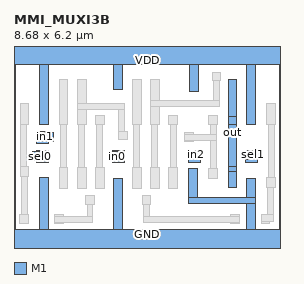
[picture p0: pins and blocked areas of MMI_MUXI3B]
MACRO MMI_MUXI3B
	CLASS CORE ;
	FOREIGN MMI_MUXI3B 0 0 ;
	SIZE 8.68 BY 6.2 ;
	SYMMETRY X Y ;
	SITE CORE1 ;
	PIN out
		DIRECTION output ;
		USE SIGNAL ;
		PORT
			LAYER M1 ;
			RECT 6.995 4.1 7.275 5.29 ;
			LAYER M1 ;
			RECT 6.985 3.82 7.275 4.1 ;
			LAYER M1 ;
			RECT 6.985 2.475 7.27 3.82 ;
			LAYER M1 ;
			RECT 6.985 2.305 7.275 2.475 ;
			LAYER M1 ;
			RECT 6.995 1.78 7.275 2.305 ;
		END
		AntennaDiffArea 0.910475 ;
	END out
	PIN sel0
		DIRECTION input ;
		USE SIGNAL ;
		PORT
			LAYER M1 ;
			RECT 0.74 2.945 1.12 2.98 ;
			LAYER M1 ;
			RECT 0.605 2.665 1.12 2.945 ;
			LAYER M1 ;
			RECT 0.74 2.6 1.12 2.665 ;
		END
		AntennaGateArea 0.51975 ;
	END sel0
	PIN in1
		DIRECTION input ;
		USE SIGNAL ;
		PORT
			LAYER M1 ;
			RECT 0.74 3.57 1.12 3.6 ;
			LAYER M1 ;
			RECT 0.74 3.29 1.285 3.57 ;
			LAYER M1 ;
			RECT 0.74 3.22 1.12 3.29 ;
		END
		AntennaGateArea 0.34575 ;
	END in1
	PIN GND
		DIRECTION inout ;
		USE GROUND ;
		PORT
			LAYER M1 ;
			RECT 0.84 0.42 1.12 2.12 ;
			LAYER M1 ;
			RECT 3.25 0.42 3.53 2.065 ;
			LAYER M1 ;
			RECT 5.7 1.445 5.98 2.395 ;
			LAYER M1 ;
			RECT 7.585 1.445 7.865 2.06 ;
			LAYER M1 ;
			RECT 5.7 1.255 7.865 1.445 ;
			LAYER M1 ;
			RECT 7.585 0.42 7.865 1.255 ;
			LAYER M1 ;
			RECT 0 -0.42 8.68 0.42 ;
		END
	END GND
	PIN in2
		DIRECTION input ;
		USE SIGNAL ;
		PORT
			LAYER M1 ;
			RECT 5.895 2.98 6.175 2.99 ;
			LAYER M1 ;
			RECT 5.7 2.71 6.175 2.98 ;
			LAYER M1 ;
			RECT 5.7 2.6 6.08 2.71 ;
		END
		AntennaGateArea 0.17325 ;
	END in2
	PIN sel1
		DIRECTION input ;
		USE SIGNAL ;
		PORT
			LAYER M1 ;
			RECT 7.56 2.7 8.06 2.98 ;
			LAYER M1 ;
			RECT 7.56 2.6 7.94 2.7 ;
		END
		AntennaGateArea 0.51975 ;
	END sel1
	PIN VDD
		DIRECTION inout ;
		USE POWER ;
		PORT
			LAYER M1 ;
			RECT 0 5.78 8.68 6.62 ;
			LAYER M1 ;
			RECT 0.84 3.835 1.12 5.78 ;
			LAYER M1 ;
			RECT 3.25 4.965 3.53 5.78 ;
			LAYER M1 ;
			RECT 5.74 4.915 6.02 5.78 ;
			LAYER M1 ;
			RECT 7.585 3.82 7.865 5.78 ;
		END
	END VDD
	PIN in0
		DIRECTION input ;
		USE SIGNAL ;
		PORT
			LAYER M1 ;
			RECT 3.22 2.94 3.6 2.98 ;
			LAYER M1 ;
			RECT 3.09 2.66 3.6 2.94 ;
			LAYER M1 ;
			RECT 3.22 2.6 3.6 2.66 ;
		END
		AntennaGateArea 0.3465 ;
	END in0
	OBS
		LAYER M1 ;
		RECT 0.205 3.835 0.485 4.535 ;
		LAYER M1 ;
		RECT 1.48 3.835 1.76 5.305 ;
		LAYER M1 ;
		RECT 2.07 4.52 2.35 5.305 ;
		LAYER M1 ;
		RECT 2.07 4.325 3.615 4.52 ;
		LAYER M1 ;
		RECT 2.07 3.835 2.35 4.325 ;
		LAYER M1 ;
		RECT 2.66 3.835 2.94 4.115 ;
		LAYER M1 ;
		RECT 0.205 2.465 0.395 3.835 ;
		LAYER M1 ;
		RECT 0.205 2.15 0.485 2.465 ;
		LAYER M1 ;
		RECT 1.52 2.44 1.71 3.835 ;
		LAYER M1 ;
		RECT 2.105 2.44 2.3 3.835 ;
		LAYER M1 ;
		RECT 2.7 2.44 2.89 3.835 ;
		LAYER M1 ;
		RECT 3.425 3.62 3.615 4.325 ;
		LAYER M1 ;
		RECT 3.87 3.835 4.15 5.305 ;
		LAYER M1 ;
		RECT 4.46 4.615 4.74 5.305 ;
		LAYER M1 ;
		RECT 6.525 5.535 6.715 5.54 ;
		LAYER M1 ;
		RECT 6.47 5.255 6.75 5.535 ;
		LAYER M1 ;
		RECT 6.525 4.615 6.715 5.255 ;
		LAYER M1 ;
		RECT 4.46 4.42 6.715 4.615 ;
		LAYER M1 ;
		RECT 4.46 3.835 4.74 4.42 ;
		LAYER M1 ;
		RECT 5.05 3.835 5.33 4.115 ;
		LAYER M1 ;
		RECT 6.355 3.835 6.635 4.115 ;
		LAYER M1 ;
		RECT 3.425 3.34 3.705 3.62 ;
		LAYER M1 ;
		RECT 3.915 2.44 4.11 3.835 ;
		LAYER M1 ;
		RECT 4.5 2.44 4.69 3.835 ;
		LAYER M1 ;
		RECT 5.095 2.44 5.29 3.835 ;
		LAYER M1 ;
		RECT 5.575 3.52 5.855 3.57 ;
		LAYER M1 ;
		RECT 6.42 3.52 6.61 3.835 ;
		LAYER M1 ;
		RECT 5.575 3.325 6.61 3.52 ;
		LAYER M1 ;
		RECT 5.575 3.29 5.855 3.325 ;
		LAYER M1 ;
		RECT 0.255 0.9 0.45 2.15 ;
		LAYER M1 ;
		RECT 0.19 0.62 0.47 0.9 ;
		LAYER M1 ;
		RECT 1.48 1.74 1.76 2.44 ;
		LAYER M1 ;
		RECT 2.07 1.74 2.35 2.44 ;
		LAYER M1 ;
		RECT 2.66 1.74 2.94 2.44 ;
		LAYER M1 ;
		RECT 2.335 1.23 2.615 1.51 ;
		LAYER M1 ;
		RECT 1.325 0.84 1.605 0.9 ;
		LAYER M1 ;
		RECT 2.385 0.84 2.575 1.23 ;
		LAYER M1 ;
		RECT 1.325 0.65 2.575 0.84 ;
		LAYER M1 ;
		RECT 1.325 0.62 1.605 0.65 ;
		LAYER M1 ;
		RECT 3.87 1.74 4.15 2.44 ;
		LAYER M1 ;
		RECT 4.46 1.74 4.74 2.44 ;
		LAYER M1 ;
		RECT 5.05 1.74 5.33 2.44 ;
		LAYER M1 ;
		RECT 6.42 2.395 6.61 3.325 ;
		LAYER M1 ;
		RECT 8.24 3.82 8.52 4.52 ;
		LAYER M1 ;
		RECT 4.18 1.23 4.46 1.51 ;
		LAYER M1 ;
		RECT 6.355 2.08 6.635 2.395 ;
		LAYER M1 ;
		RECT 8.29 2.095 8.485 3.82 ;
		LAYER M1 ;
		RECT 8.24 1.78 8.52 2.095 ;
		LAYER M1 ;
		RECT 4.22 0.84 4.41 1.23 ;
		LAYER M1 ;
		RECT 7.075 0.84 7.355 0.9 ;
		LAYER M1 ;
		RECT 4.22 0.65 7.355 0.84 ;
		LAYER M1 ;
		RECT 7.075 0.62 7.355 0.65 ;
		LAYER M1 ;
		RECT 8.265 0.9 8.46 1.78 ;
		LAYER M1 ;
		RECT 8.07 0.66 8.46 0.9 ;
		LAYER M1 ;
		RECT 8.07 0.62 8.35 0.66 ;
	END
END MMI_MUXI3B
